VERSION 5.8 ;
BUSBITCHARS "[]" ;
DIVIDERCHAR "/" ;
UNITS
    DATABASE MICRONS 1000 ;
END UNITS

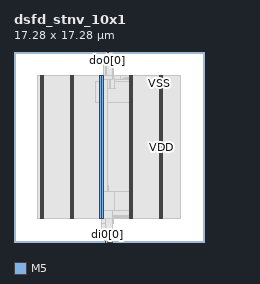
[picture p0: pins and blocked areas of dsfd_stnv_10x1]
MACRO dsfd_stnv_10x1
  FOREIGN dsfd_stnv_10x1 0 0 ;
  CLASS BLOCK ;
  SIZE 17.28 BY 17.28 ;
  PIN di0[0]
    DIRECTION INPUT ;
    USE SIGNAL ;
    PORT
      LAYER M5 ;
        RECT  8.496 0 8.52 0.084 ;
    END
  END di0[0]
  PIN di0[1]
    DIRECTION INPUT ;
    USE SIGNAL ;
    PORT
      LAYER M5 ;
        RECT  8.544 0 8.568 0.084 ;
    END
  END di0[1]
  PIN di0[2]
    DIRECTION INPUT ;
    USE SIGNAL ;
    PORT
      LAYER M5 ;
        RECT  8.592 0 8.616 0.084 ;
    END
  END di0[2]
  PIN di0[3]
    DIRECTION INPUT ;
    USE SIGNAL ;
    PORT
      LAYER M5 ;
        RECT  8.64 0 8.664 0.084 ;
    END
  END di0[3]
  PIN di0[4]
    DIRECTION INPUT ;
    USE SIGNAL ;
    PORT
      LAYER M5 ;
        RECT  8.688 0 8.712 0.084 ;
    END
  END di0[4]
  PIN di0[5]
    DIRECTION INPUT ;
    USE SIGNAL ;
    PORT
      LAYER M5 ;
        RECT  8.736 0 8.76 0.084 ;
    END
  END di0[5]
  PIN di0[6]
    DIRECTION INPUT ;
    USE SIGNAL ;
    PORT
      LAYER M5 ;
        RECT  8.784 0 8.808 0.084 ;
    END
  END di0[6]
  PIN di0[7]
    DIRECTION INPUT ;
    USE SIGNAL ;
    PORT
      LAYER M5 ;
        RECT  8.832 0 8.856 0.084 ;
    END
  END di0[7]
  PIN di0[8]
    DIRECTION INPUT ;
    USE SIGNAL ;
    PORT
      LAYER M5 ;
        RECT  8.88 0 8.904 0.084 ;
    END
  END di0[8]
  PIN di0[9]
    DIRECTION INPUT ;
    USE SIGNAL ;
    PORT
      LAYER M5 ;
        RECT  8.928 0 8.952 0.084 ;
    END
  END di0[9]
  PIN do0[0]
    DIRECTION OUTPUT ;
    USE SIGNAL ;
    PORT
      LAYER M5 ;
        RECT  8.496 17.196 8.52 17.28 ;
    END
  END do0[0]
  PIN do0[1]
    DIRECTION OUTPUT ;
    USE SIGNAL ;
    PORT
      LAYER M5 ;
        RECT  8.544 17.196 8.568 17.28 ;
    END
  END do0[1]
  PIN do0[2]
    DIRECTION OUTPUT ;
    USE SIGNAL ;
    PORT
      LAYER M5 ;
        RECT  8.592 17.196 8.616 17.28 ;
    END
  END do0[2]
  PIN do0[3]
    DIRECTION OUTPUT ;
    USE SIGNAL ;
    PORT
      LAYER M5 ;
        RECT  8.64 17.196 8.664 17.28 ;
    END
  END do0[3]
  PIN do0[4]
    DIRECTION OUTPUT ;
    USE SIGNAL ;
    PORT
      LAYER M5 ;
        RECT  8.688 17.196 8.712 17.28 ;
    END
  END do0[4]
  PIN do0[5]
    DIRECTION OUTPUT ;
    USE SIGNAL ;
    PORT
      LAYER M5 ;
        RECT  8.736 17.196 8.76 17.28 ;
    END
  END do0[5]
  PIN do0[6]
    DIRECTION OUTPUT ;
    USE SIGNAL ;
    PORT
      LAYER M5 ;
        RECT  8.784 17.196 8.808 17.28 ;
    END
  END do0[6]
  PIN do0[7]
    DIRECTION OUTPUT ;
    USE SIGNAL ;
    PORT
      LAYER M5 ;
        RECT  8.832 17.196 8.856 17.28 ;
    END
  END do0[7]
  PIN do0[8]
    DIRECTION OUTPUT ;
    USE SIGNAL ;
    PORT
      LAYER M5 ;
        RECT  8.88 17.196 8.904 17.28 ;
    END
  END do0[8]
  PIN do0[9]
    DIRECTION OUTPUT ;
    USE SIGNAL ;
    PORT
      LAYER M5 ;
        RECT  8.928 17.196 8.952 17.28 ;
    END
  END do0[9]
  PIN fi0[0]
    DIRECTION INPUT ;
    USE SIGNAL ;
    PORT
      LAYER M5 ;
        RECT  8.304 0 8.328 0.084 ;
    END
  END fi0[0]
  PIN fo0[0]
    DIRECTION OUTPUT ;
    USE SIGNAL ;
    PORT
      LAYER M5 ;
        RECT  8.304 17.196 8.328 17.28 ;
    END
  END fo0[0]
  PIN VDD
    DIRECTION INOUT ;
    USE POWER ;
    PORT
      LAYER M5 ;
        RECT  13.392 2.151 13.512 15.129 ;
        RECT  10.692 2.151 10.812 15.129 ;
        RECT  7.992 2.151 8.112 15.129 ;
        RECT  5.292 2.151 5.412 15.129 ;
        RECT  2.592 2.151 2.712 15.129 ;
    END
  END VDD
  PIN VSS
    DIRECTION INOUT ;
    USE GROUND ;
    PORT
      LAYER M5 ;
        RECT  13.2 2.137 13.32 15.143 ;
        RECT  10.5 2.137 10.62 15.143 ;
        RECT  7.8 2.137 7.92 15.143 ;
        RECT  5.1 2.137 5.22 15.143 ;
        RECT  2.4 2.137 2.52 15.143 ;
    END
  END VSS
  # OT_OBS_CLOSED layer=M5 d_um=1.536 added=2
  OBS
    LAYER RVTN ;
     RECT  2.16 2.16 15.12 2.295 ;
     RECT  2.16 2.565 15.12 2.835 ;
     RECT  2.16 3.105 15.12 3.375 ;
     RECT  2.16 3.645 15.12 3.915 ;
     RECT  2.16 4.185 15.12 4.455 ;
     RECT  2.16 4.725 15.12 4.995 ;
     RECT  2.16 5.265 15.12 5.535 ;
     RECT  2.16 5.805 15.12 6.075 ;
     RECT  2.16 6.345 15.12 6.615 ;
     RECT  2.16 6.885 15.12 7.155 ;
     RECT  2.16 7.425 15.12 7.695 ;
     RECT  2.16 7.965 15.12 8.235 ;
     RECT  2.16 8.505 15.12 8.775 ;
     RECT  2.16 9.045 15.12 9.315 ;
     RECT  2.16 9.585 15.12 9.855 ;
     RECT  2.16 10.125 15.12 10.395 ;
     RECT  2.16 10.665 15.12 10.935 ;
     RECT  2.16 11.205 15.12 11.475 ;
     RECT  2.16 11.745 15.12 12.015 ;
     RECT  2.16 12.285 15.12 12.555 ;
     RECT  2.16 12.825 15.12 13.095 ;
     RECT  2.16 13.365 15.12 13.635 ;
     RECT  2.16 13.905 15.12 14.175 ;
     RECT  2.16 14.445 15.12 14.715 ;
     RECT  2.16 14.985 15.12 15.12 ;
    LAYER RVTP ;
     RECT  2.16 2.295 15.12 2.565 ;
     RECT  2.16 2.835 15.12 3.105 ;
     RECT  2.16 3.375 15.12 3.645 ;
     RECT  2.16 3.915 15.12 4.185 ;
     RECT  2.16 4.455 15.12 4.725 ;
     RECT  2.16 4.995 15.12 5.265 ;
     RECT  2.16 5.535 15.12 5.805 ;
     RECT  2.16 6.075 15.12 6.345 ;
     RECT  2.16 6.615 15.12 6.885 ;
     RECT  2.16 7.155 15.12 7.425 ;
     RECT  2.16 7.695 15.12 7.965 ;
     RECT  2.16 8.235 15.12 8.505 ;
     RECT  2.16 8.775 15.12 9.045 ;
     RECT  2.16 9.315 15.12 9.585 ;
     RECT  2.16 9.855 15.12 10.125 ;
     RECT  2.16 10.395 15.12 10.665 ;
     RECT  2.16 10.935 15.12 11.205 ;
     RECT  2.16 11.475 15.12 11.745 ;
     RECT  2.16 12.015 15.12 12.285 ;
     RECT  2.16 12.555 15.12 12.825 ;
     RECT  2.16 13.095 15.12 13.365 ;
     RECT  2.16 13.635 15.12 13.905 ;
     RECT  2.16 14.175 15.12 14.445 ;
     RECT  2.16 14.715 15.12 14.985 ;
    LAYER M1 ;
     RECT  2.16 2.151 15.12 15.129 ;
    LAYER M2 ;
     RECT  2.16 2.151 7.771 15.129 ;
     RECT  7.771 2.106 9.671 15.129 ;
     RECT  9.671 2.151 15.12 15.129 ;
    LAYER M3 ;
     RECT  8.28 0.139 8.298 0.187 ;
     RECT  8.28 0.187 8.514 0.571 ;
     RECT  7.992 0.571 8.514 0.619 ;
     RECT  7.992 0.619 8.586 1.723 ;
     RECT  7.992 1.723 9.018 2.101 ;
     RECT  7.776 2.101 9.666 2.191 ;
     RECT  10.515 2.143 10.605 2.191 ;
     RECT  7.776 2.191 10.605 2.291 ;
     RECT  2.415 2.143 2.505 2.413 ;
     RECT  5.115 2.143 5.205 2.413 ;
     RECT  7.815 2.291 10.605 2.413 ;
     RECT  13.215 2.143 13.305 2.413 ;
     RECT  7.815 2.413 10.797 12.721 ;
     RECT  7.416 12.721 10.797 14.639 ;
     RECT  7.74 14.639 10.797 14.819 ;
     RECT  2.415 2.413 2.697 14.867 ;
     RECT  5.115 2.413 5.397 14.867 ;
     RECT  9.9 14.819 10.797 14.867 ;
     RECT  13.215 2.413 13.497 14.867 ;
     RECT  7.74 14.819 9.126 14.909 ;
     RECT  9.9 14.867 10.638 14.909 ;
     RECT  10.08 14.909 10.605 14.981 ;
     RECT  10.476 14.981 10.605 15.089 ;
     RECT  2.415 14.867 2.505 15.137 ;
     RECT  5.115 14.867 5.205 15.137 ;
     RECT  7.815 14.909 9.054 15.137 ;
     RECT  10.515 15.089 10.605 15.137 ;
     RECT  13.215 14.867 13.305 15.137 ;
     RECT  8.136 15.137 9.054 16.589 ;
     RECT  8.496 16.589 9.054 16.829 ;
     RECT  9.036 16.829 9.054 17.117 ;
    LAYER M4 ;
     RECT  2.408 2.148 2.512 15.132 ;
     RECT  2.512 2.418 2.704 14.862 ;
     RECT  5.108 2.148 5.212 15.132 ;
     RECT  5.212 2.418 5.404 14.862 ;
     RECT  7.808 2.148 8.104 15.132 ;
     RECT  7.981 0.576 8.269 0.6 ;
     RECT  8.125 16.56 8.293 16.584 ;
     RECT  8.104 13.968 8.377 15.132 ;
     RECT  8.293 16.512 8.377 16.584 ;
     RECT  8.377 13.968 8.437 16.584 ;
     RECT  8.437 13.968 8.485 16.68 ;
     RECT  8.269 0.144 8.53 0.6 ;
     RECT  8.104 4.56 8.569 5.112 ;
     RECT  8.53 0.144 8.579 0.648 ;
     RECT  8.104 2.148 8.621 3.432 ;
     RECT  8.579 0.192 8.641 0.648 ;
     RECT  8.485 13.968 8.675 16.824 ;
     RECT  8.675 13.968 8.741 15.96 ;
     RECT  8.741 13.968 8.812 15.912 ;
     RECT  8.641 0.192 8.867 0.216 ;
     RECT  8.621 1.728 8.993 3.432 ;
     RECT  8.993 1.728 9.029 1.752 ;
     RECT  8.812 15.888 9.029 15.912 ;
     RECT  8.869 17.088 9.065 17.112 ;
     RECT  8.569 4.56 9.107 4.584 ;
     RECT  8.812 13.968 9.137 14.904 ;
     RECT  9.137 13.968 9.209 13.992 ;
     RECT  8.993 2.832 10.508 3.432 ;
     RECT  10.508 2.148 10.612 15.132 ;
     RECT  10.612 2.418 10.804 14.862 ;
     RECT  13.208 2.148 13.312 15.132 ;
     RECT  13.312 2.418 13.504 14.862 ;
    LAYER M5 ;
     RECT  8.304 0.016 8.952 2.137 ;
     RECT  2.4 2.137 2.52 2.151 ;
     RECT  5.1 2.137 5.22 2.151 ;
     RECT  10.5 2.137 10.62 2.151 ;
     RECT  13.2 2.137 13.32 2.151 ;
     RECT  7.8 2.137 8.952 2.821 ;
     RECT  7.8 2.821 9.096 4.595 ;
     RECT  7.8 4.595 8.52 14.773 ;
     RECT  7.8 14.773 8.808 14.821 ;
     RECT  2.4 2.151 2.712 15.129 ;
     RECT  5.1 2.151 5.412 15.129 ;
     RECT  10.5 2.151 10.812 15.129 ;
     RECT  13.2 2.151 13.512 15.129 ;
     RECT  2.4 15.129 2.52 15.143 ;
     RECT  5.1 15.129 5.22 15.143 ;
     RECT  7.8 14.821 8.952 15.143 ;
     RECT  10.5 15.129 10.62 15.143 ;
     RECT  13.2 15.129 13.32 15.143 ;
     RECT  8.448 15.143 8.952 16.501 ;
     RECT  8.304 16.501 8.952 17.232 ;
     RECT  9.096 2.821 10.5 4.595 ;
     RECT  8.304 15.143 8.448 16.501 ;
  END
END dsfd_stnv_10x1
END LIBRARY
